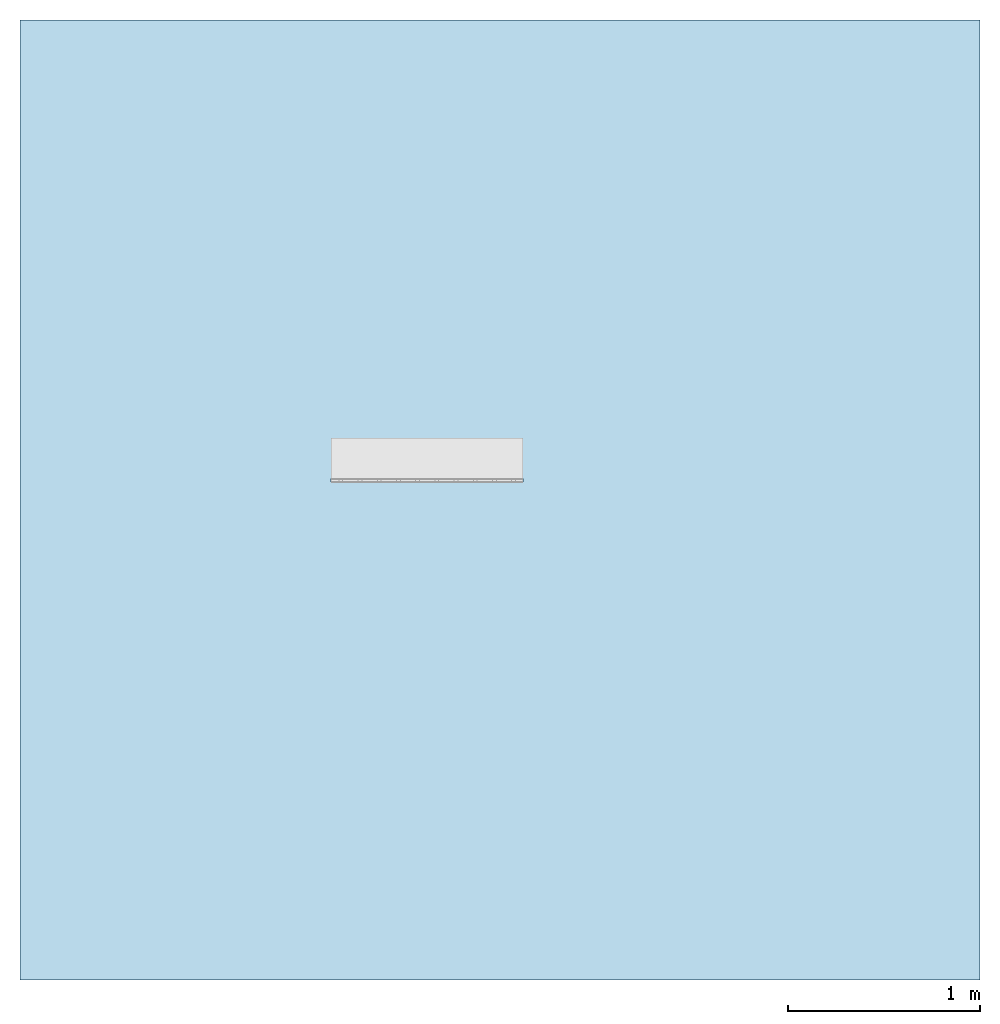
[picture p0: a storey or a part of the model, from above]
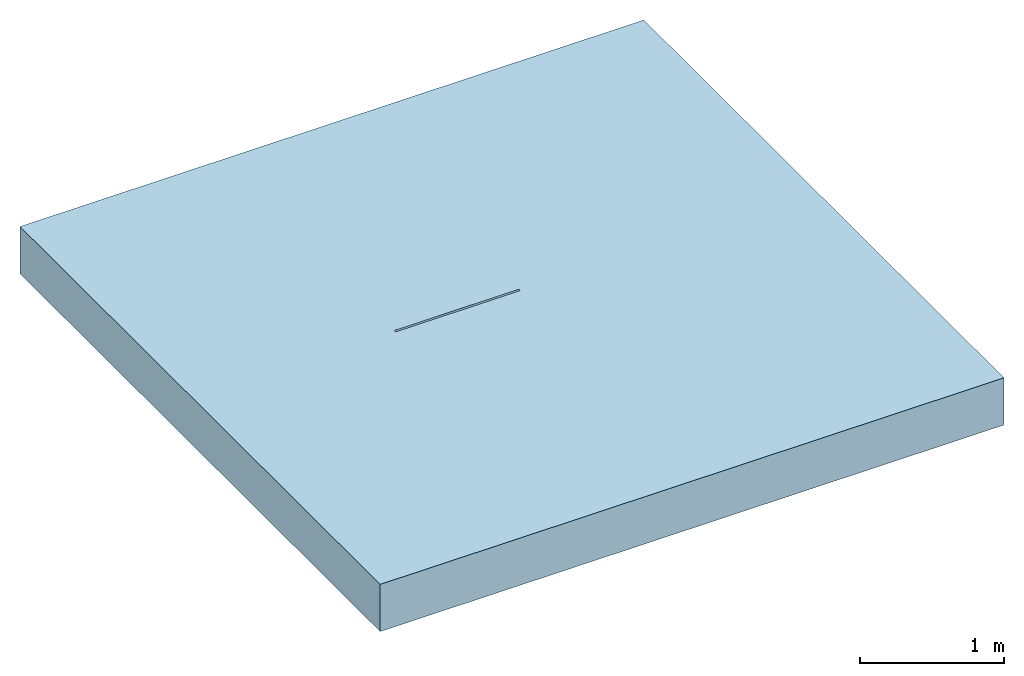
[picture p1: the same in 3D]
Properties of the parts of a building model (IFC2X3)

# File
Description: ViewDefinition [CoordinationView]
File name: 24212 - No 20.0 Constant Depth Channel - 1000mm LG - Invert Depth 340mm.ifc
Time: 2013-10-30T14:05:29
Written by: Autodesk Revit 2013
Made in: 20120221_2030(x64)

# IfcProject, Project Number
LongName: Project Name; Phase: Project Status

# IfcSite, Default
RefLatitude: 42, 21, 30, 344238; RefLongitude: -71, -3, -35, -194702; RefElevation: 0 mm

# IfcBuilding
Pset_BuildingCommon - NumberOfStoreys: 1
Other - Project Name: Project Name; Project Number: Project Number; Client Name: Owner; Project Status: Project Status; Project Address: ## Street City, State Zip; Project Issue Date: Issue Date

# IfcBuildingStorey, Level 1
LongName: Level 1; Elevation: 0 mm
Constraints - Elevation Base: 0; Elevation: 0 mm
Graphics - Symbol: M_Level Head - Circle: M_Level Head - Circle; Line Weight: 1; Line Pattern: Center; Color: 0; Symbol at End 1 Default: no; Symbol at End 2 Default: yes
Identity Data - Structural: no; Building Story: yes; Name: Level 1
Dimensions - Computation Height: 0 mm

# IfcBuildingElementProxy: 24212 - No 20.0 Constant Depth Channel - 1000mm LG - Invert Depth 340mm, Civil-Drainage-Channel-ACO-MultiDrain-M200DS-Brickslot-Channel-System:24212 - No 20.0 Constant Depth Channel - 1000mm LG - Invert Depth 340mm:24212 - No 20.0 Constant Depth Channel - 1000mm LG - Invert Depth 340mm:196059
In: Level 1
Material: Stainless Steel (F), Vienite® Synthetic Resin Concrete
Construction - 408999_Load Class C250 & D400_Brickslot Grating_Stainless Steel_500mm Long: no; 408998_Load Class C250 & D400_Brickslot Grating_Stainless Steel_1000mm Long: yes; 23219 - Universal Endcap (Female End): no; 23219 - Universal Endcap (Male End): no; 409000_Load Class C250 & D400_Brickslot_Access Unit_Stainless Steel_500mm Long: no; 23410_Sump Unit: no; Constant Depth Channel_500: no; Constant Depth Channel_1000: yes; Shallow Depth Channel with seal: no; Shallow Depth Channel: no
Dimensions - Brickslot Grating Void Depth: 0 mm; Brickslot Access Unit Void Depth: 6000 mm; Brickslot Void Length: -1000 mm; Brickslot Access Unit Void Bottom Depth: 6105 mm; Custom_Void_Length: 0 mm; EndCap Position: 1000 mm; Length: 1000 mm; FloorCut_Length: -1000 mm; Volume: 22555290 mm3; FloorCut_Depth: 365 mm; EndCap_Height: 365 mm; Depth: 365 mm; InvDepth: 240 mm; Length Drain: -1000 mm; FloorCut_HorPosition: 117.5 mm; FloorCut_Width: 235 mm
Constraints - Moves With Nearby Elements: no; Level: Level: Level 1
Phasing - Phase Created: New Construction
Pset_BuildingElementProxyCommon - Reference: 24212 - No 20.0 Constant Depth Channel - 1000mm LG - Invert Depth 340mm
Data - Product Standard: BS EN 1433:2002, CE marked; Installation - Concrete Grade: Refer to brochure; Concrete Surround Volume - Load Class D 400 - Concrete Pavement: 0.29m³/m; Hydraulic Performance: http://www.aco.co.uk/download.php?id=173; Channel C.S.A: 0.051m²; ACO Hydraulic Design Software: http://www.acodesign.co.uk; Invert Depth: 340mm; Concrete Surround Volume - Load Class B 125 - C 250 - Concrete Pavement: 0.20m³/m; Load Class: A 15 - D 400; Product Dimensions: 1000mm x 235mm x 365mm (LxWxH); Concrete Surround Volume - Load Class A 15 - Concrete Pavement: 0.13m³/m; Product Weight: 39.4 Kg
Identity Data - Watermarked By: www.aco.co.uk; Price: POA - contact ACO; Product Page URL: http://www.aco.co.uk/product_detail.php?id=58; Installation guidelines: http://www.aco.co.uk/download.php?id=173; Watermarked With: BIM Manager Premium Suite; Address: ACO Business Park, Hitchin Road, Shefford, Bedfordshire, United Kingdom SG17 5TE; Assembly Description: Rain Water Drainage; e-mail Sales: customersupport@aco.co.uk; Watermark 1: This file is the property of ACO Technologies PLC; Product Code: 24212; Type Comments: ACO MultiDrain M200DS 20.0 Constant Depth Channel 1000mm Long; OmniClass Title: Rainwater Removal; Watermark 2: This file is water marked and users are prohibited to reproduce, adapt, distribute this information; Model: ACO MultiDrain MDS Brickslot - M200DS; Product brochure: http://www.aco.co.uk/download.php?id=173; OmniClass Number: 23.70.50.24; e-mail Technical: technical@aco.co.uk; Cost: 0; Manufacturer: ACO Technologies plc - ACO Water Management Division; Model Description: Channel drainage system; Fax: +44 (0)1462 815895; URL: www.aco.co.uk; Assembly Code: D2040; Telephone: +44 (0)1462 816666; Maintenance guidelines: http://www.aco.co.uk/download.php?id=173
General - TagNumber: 0; SerialNumber: 0
Green Building Properties - Edge Rail Recycled Material Content: Between 40% - 90%; Channel Recyclable: Fully recyclable; Edge Rail Recyclable: Fully recyclable; Channel Recycled Material Content: 20% minimum
Materials and Finishes - Channel Material: Vienite® Synthetic Resin Concrete; Edge Rail Colour: Self; Edge Rail Material: Stainless Steel Grade 304; Channel Colour: Brown
Model Properties - End Cap Product code 23219: No 306 Universal End Cap - 235mm wide x 365mm long - Spigot Ø160mm x 75mm long - Silver - Polypropylene - 0.4kg; Brickslot Grating Product code 408998: Load Class C250/D400 - Brickslot Stainless Steel - 1000mm long x 105mm high - 10mm Slot - Intake area 10000mm²/m - 9.8kg; Brickslot Grating Product code 408999: Load Class C250/D400 - Brickslot Stainless Steel - 500mm long x 105mm high - 10mm Slot - Intake area 10000mm²/m - 4.8kg; Brickslot Access Unit Product code 409000: Load Class C250/D400 - Brickslot Access Unit Stainless Steel - 500mm long x 105mm high - 10mm Slot - Intake area 10000mm²/m - 8.5 Kg
Other - Revision: 1; CreatedBy: www.aco.co.uk

# IfcOpeningElement: Opening (2)
In: Level 1
Constraints - Room Bounding: yes; Level: Level: Level 1; Related to Mass: no; Height Offset From Level: 0 mm
Phasing - Phase Created: New Construction
Dimensions - Area: 24982000 mm2; Thickness: 400 mm; Volume: 9928785000 mm3; Perimeter: 20000 mm
Structural - Structural: no; Enable Analytical Model: no
Graphics - Coarse Scale Fill Color: 0
Construction - Default Thickness: 400 mm; Function: 0
Analytical Properties - Thermal Resistance (R): 0.477897; Thermal mass: 543920; Heat Transfer Coefficient (U): 2.0925; Roughness: 1; Absorptance: 0.1
Materials and Finishes - Structural Material: Earth

# IfcSlab: Floor:Generic Floor - 400mm, Floor:Generic Floor - 400mm:193825
In: Level 1
PredefinedType: FLOOR; Material: Earth 400 mm
Constraints - Room Bounding: yes; Level: Level: Level 1; Related to Mass: no; Height Offset From Level: 0 mm
Phasing - Phase Created: New Construction
Dimensions - Area: 24982000 mm2; Thickness: 400 mm; Volume: 9928785000 mm3; Perimeter: 20000 mm
Structural - Structural: no; Enable Analytical Model: no
Pset_SlabCommon - Reference: Generic Floor - 400mm; IsExternal: no; LoadBearing: yes
Graphics - Coarse Scale Fill Color: 0
Construction - Default Thickness: 400 mm; Function: 0
Analytical Properties - Thermal Resistance (R): 0.477897; Thermal mass: 543920; Heat Transfer Coefficient (U): 2.0925; Roughness: 1; Absorptance: 0.1
Materials and Finishes - Structural Material: Earth
